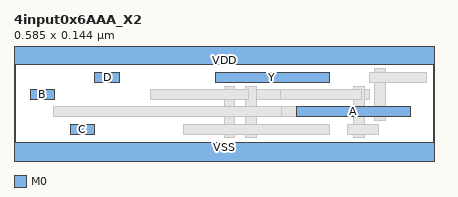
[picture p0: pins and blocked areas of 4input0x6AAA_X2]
MACRO 4input0x6AAA_X2
  CLASS CORE ;
  ORIGIN 0 0 ;
  FOREIGN 4input0x6AAA_X2 0 0 ;
  SIZE 0.5850 BY 0.1440 ;
  SYMMETRY X Y ;
  SITE coresite ;
  PIN A
    DIRECTION INPUT ;
    USE SIGNAL ;
    PORT
      LAYER M0 ;
        RECT 0.3930 0.0530 0.5520 0.0670 ;
    END
  END A
  PIN B
    DIRECTION INPUT ;
    USE SIGNAL ;
    PORT
      LAYER M0 ;
        RECT 0.0225 0.0770 0.0570 0.0910 ;
    END
  END B
  PIN C
    DIRECTION INPUT ;
    USE SIGNAL ;
    PORT
      LAYER M0 ;
        RECT 0.0780 0.0290 0.1125 0.0430 ;
    END
  END C
  PIN D
    DIRECTION INPUT ;
    USE SIGNAL ;
    PORT
      LAYER M0 ;
        RECT 0.1125 0.1010 0.1470 0.1150 ;
    END
  END D
  PIN Y
    DIRECTION OUTPUT ;
    USE SIGNAL ;
    PORT
      LAYER M0 ;
        RECT 0.2805 0.1010 0.4395 0.1150 ;
    END
  END Y
  PIN VDD
    DIRECTION INOUT ;
    USE POWER ;
    SHAPE ABUTMENT ;
    PORT
      LAYER M0 ;
        RECT 0.0000 0.1260 0.5850 0.1620 ;
    END
  END VDD
  PIN VSS
    DIRECTION INOUT ;
    USE GROUND ;
    SHAPE ABUTMENT ;
    PORT
      LAYER M0 ;
        RECT 0.0000 -0.0180 0.5850 0.0180 ;
    END
  END VSS
  OBS
    LAYER V1 ;
      RECT 0.2930 0.0530 0.3070 0.0670 ;
      RECT 0.5030 0.0530 0.5170 0.0670 ;
      RECT 0.3230 0.0770 0.3370 0.0910 ;
      RECT 0.4730 0.0770 0.4870 0.0910 ;
    LAYER M2 ;
      RECT 0.2880 0.0530 0.5220 0.0670 ;
      RECT 0.3150 0.0770 0.4950 0.0910 ;
    LAYER V0 ;
      RECT 0.2930 0.0770 0.3070 0.0910 ;
      RECT 0.5030 0.1010 0.5170 0.1150 ;
      RECT 0.3230 0.0530 0.3370 0.0670 ;
      RECT 0.4730 0.0290 0.4870 0.0430 ;
    LAYER M1 ;
      RECT 0.2925 0.0240 0.3075 0.0960 ;
      RECT 0.3225 0.0240 0.3375 0.0960 ;
      RECT 0.4725 0.0240 0.4875 0.0960 ;
      RECT 0.5025 0.0480 0.5175 0.1200 ;
    LAYER M0 ;
      RECT 0.2355 0.0290 0.4395 0.0430 ;
      RECT 0.4650 0.0290 0.5070 0.0430 ;
      RECT 0.0555 0.0530 0.3720 0.0670 ;
      RECT 0.1905 0.0770 0.3270 0.0910 ;
      RECT 0.3705 0.0770 0.4845 0.0910 ;
      RECT 0.4950 0.1010 0.5745 0.1150 ;
  END
END 4input0x6AAA_X2
